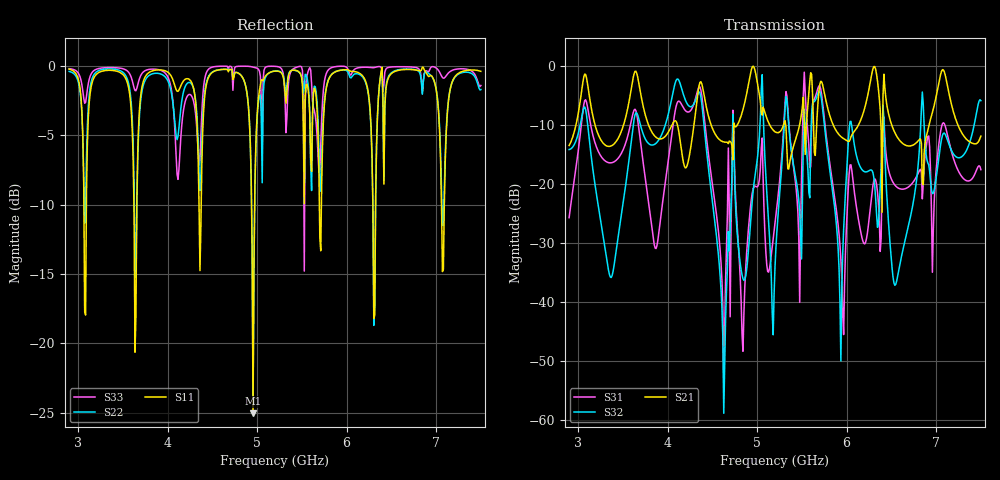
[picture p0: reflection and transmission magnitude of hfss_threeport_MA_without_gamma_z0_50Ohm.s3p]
! Touchstone file from project Project1
! Exported from HFSS 2017.1.0
# GHZ S MA R 50.000000
! Modal data exported
! Port[1] = 1:1
! Port[2] = 2:1
! Port[3] = 3:1
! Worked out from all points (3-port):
!   451 points, 2.9 GHz to 7.5 GHz, reference 50 ohm
!   strongest paths, dB at 2.9 GHz, 4.045 GHz, 5.2 GHz, 6.355 GHz, 7.5 GHz:
!     S21: -13.5, -10.1, -11.2, -3.9, -11.9
!     S32: -14.2, -5.6, -34.1, -26.8, -5.9
!     S31: -25.7, -11.8, -26.7, -23.2, -17.6
!   lowest |S11| = -25.0 dB at 4.955 GHz (marker M1), VSWR 1.12, Z = 44.9 - j1.58 ohm
!   |S11| at or under -10 dB: 3.624 GHz to 3.656 GHz (32.06 MHz wide, 0.881 % of centre); 4.938 GHz to 4.973 GHz (34.94 MHz wide, 0.705 % of centre); 7.059955 GHz to 7.091402 GHz (31.45 MHz wide, 0.444 % of centre) (the widest 3 of 7)
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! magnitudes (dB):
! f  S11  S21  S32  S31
! 2.9 GHz  -0.2  -13.5  -14.2  -25.7
! 4.352 GHz  -10.1  -3.4  -4.4  -3.5
! 4.628 GHz  -0.2  -12.9  -58.8  -53.4
! 4.955 GHz  -25.0  0.0  -21.4  -20.9
! 5.2 GHz  -0.4  -11.2  -34.1  -26.7
! 5.323 GHz  -2.7  -10.3  -5.2  -4.4
! 5.936 GHz  -0.3  -12.0  -49.9  -32.7
! 6.048 GHz  -0.4  -12.0  -9.4  -16.7
! 6.549 GHz  -0.4  -11.6  -37.0  -20.3
! 7.5 GHz  -0.4  -11.9  -5.9  -17.6
